VERSION 5.8 ;
BUSBITCHARS "[]" ;
DIVIDERCHAR "/" ;
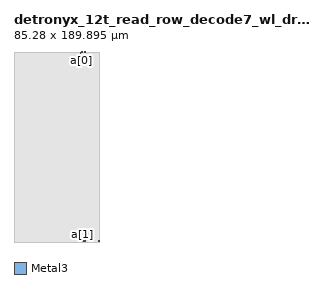
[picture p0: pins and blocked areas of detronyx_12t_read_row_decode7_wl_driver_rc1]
MACRO detronyx_12t_read_row_decode7_wl_driver_rc1
  CLASS BLOCK ;
  FOREIGN detronyx_12t_read_row_decode7_wl_driver_rc1 0.000 0.000 ;
  ORIGIN 0.000 0.000 ;
  SIZE 85.280000 BY 189.895000 ;
  SYMMETRY X Y ;
  PIN VDD
    DIRECTION INOUT ;
    USE POWER ;
    PORT
      LAYER Metal3 ;
        RECT 66.500000 188.695000 66.860000 189.895000 ;
    END
  END VDD
  PIN VSS
    DIRECTION INOUT ;
    USE GROUND ;
    PORT
      LAYER Metal3 ;
        RECT 65.800000 0.700000 66.160000 1.900000 ;
    END
  END VSS
  PIN ren
    DIRECTION INPUT ;
    USE SIGNAL ;
    PORT
      LAYER Metal3 ;
        RECT 84.700000 0.700000 85.060000 1.500000 ;
    END
  END ren
  PIN a[0]
    DIRECTION INPUT ;
    USE SIGNAL ;
    PORT
      LAYER Metal3 ;
        RECT 67.200000 189.795000 67.560000 190.595000 ;
    END
  END a[0]
  PIN a[1]
    DIRECTION INPUT ;
    USE SIGNAL ;
    PORT
      LAYER Metal3 ;
        RECT 67.900000 0.700000 68.260000 1.500000 ;
    END
  END a[1]
  PIN a[2]
    DIRECTION INPUT ;
    USE SIGNAL ;
    PORT
      LAYER Metal3 ;
        RECT 68.600000 189.795000 68.960000 190.595000 ;
    END
  END a[2]
  PIN a[3]
    DIRECTION INPUT ;
    USE SIGNAL ;
    PORT
      LAYER Metal3 ;
        RECT 69.300000 0.700000 69.660000 1.500000 ;
    END
  END a[3]
  PIN a[4]
    DIRECTION INPUT ;
    USE SIGNAL ;
    PORT
      LAYER Metal3 ;
        RECT 70.000000 189.795000 70.360000 190.595000 ;
    END
  END a[4]
  PIN a[5]
    DIRECTION INPUT ;
    USE SIGNAL ;
    PORT
      LAYER Metal3 ;
        RECT 70.700000 0.700000 71.060000 1.500000 ;
    END
  END a[5]
  PIN a[6]
    DIRECTION INPUT ;
    USE SIGNAL ;
    PORT
      LAYER Metal3 ;
        RECT 71.400000 189.795000 71.760000 190.595000 ;
    END
  END a[6]
  PIN rwl0
    DIRECTION OUTPUT ;
    USE SIGNAL ;
    PORT
      LAYER Metal3 ;
        RECT 85.400000 0.700000 85.760000 1.500000 ;
    END
  END rwl0
  OBS
    LAYER Metal1 ;
      RECT 0.000000 0.000000 85.280000 189.895000 ;
    LAYER Metal2 ;
      RECT 0.000000 0.000000 85.280000 189.895000 ;
  END
END detronyx_12t_read_row_decode7_wl_driver_rc1
END LIBRARY
